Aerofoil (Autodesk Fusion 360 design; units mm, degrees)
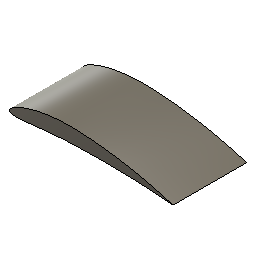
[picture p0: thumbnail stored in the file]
sketch "Sketch1"
extrude "Extrude1" new body sketch "Sketch1" blind 4.5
